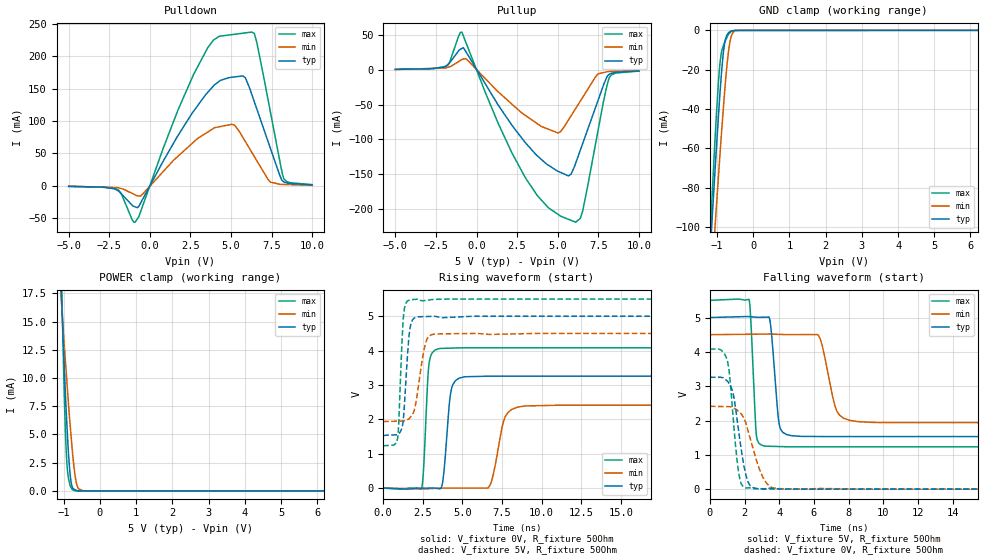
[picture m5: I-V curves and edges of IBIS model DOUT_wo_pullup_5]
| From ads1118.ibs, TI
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|   DOUT Model 5 V model Config Register bit3=1
[Model] DOUT_wo_pullup_5
|  Signals  DOUT/_DRDY(9)
|   bit 3 of the Config Registor is one
Model_type   3-state
Polarity   Non-Inverting
Enable   Active-Low
Vmeas = 2.5
Vref = 2.5
Cref = 15pF
Rref = 50
|   typ   min   max
|   (nom PVT)   (Fast PVT)   (slow PVT)
C_comp   1.8850880e-12  1.5248640e-12  2.2687600e-12
|   typ   min   max
|   (nom PVT)   (slow PVT)   (Fast PVT)
|C_comp (ON state)   2.6065280e-12  2.2751560e-12  4.1907400e-12
|C_comp (OFF state)   2.4127670e-12  2.2979320e-12  3.1339800e-12
| Where   nom PVT is  Nominal Process, 5V, 27C
|   Fast PVT is Strong or Fast Process, 5.5V, -40C
|   Slow PVT is Weak or Slow Process, 4.5V, 125C
| variable   typ   min   max
[Voltage Range]   5   4.5   5.5
|Operating Temperature   27   125   -40
[Temperature Range]   27   125   -40
[Pullup Reference]   5   4.5   5.5
[Pulldown Reference]   0   0   0
[Power Clamp Reference]   5   4.5   5.5
[GND Clamp Reference]   0   0   0
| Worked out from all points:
|   slope of the pulldown table from 0 to 0.75 V, typ, clamps not added: 21.6 ohm
|   slope of the pullup table from 0 to 0.75 V, typ, clamps not added: 25.9 ohm
|   GND clamp passes 1 mA (typ) near -0.67 V on its own axis
|   POWER clamp passes 1 mA (typ) near -0.81 V on its own axis
|   falling waveform, V_fixture 5V, R_fixture 50Ohm: 20-80 % time 327ps typ, 636ps min, 228ps max; typ from 5 V to 1.53 V
|   rising waveform, V_fixture 0V, R_fixture 50Ohm: 20-80 % time 342ps typ, 600ps min, 247ps max; typ from 0 V to 3.26 V
|   rising waveform, V_fixture 5V, R_fixture 50Ohm: 20-80 % time 296ps typ, 513ps min, 232ps max; typ from 1.53 V to 5 V
|   falling waveform, V_fixture 0V, R_fixture 50Ohm: 20-80 % time 566ps typ, 869ps min, 426ps max; typ from 3.26 V to 0 V
[Pulldown]
|   Voltage   I(typ)   I(min)   I(max)
-5V       -725.4uA   -519.1uA   -702.6uA
-1.982V   -7.151mA   -2.66mA    -5.43mA
-909.4mV  -32.26mA   -13.86mA   -55.8mA
1.742V    78.01mA    45.92mA    117.6mA
3.541V    143.5mA    82.63mA    211.9mA
5.072V    167.5mA    95.02mA    233.1mA
5.878V    166.7mA    68.45mA    235.8mA
6.259V    142.2mA    52.51mA    237mA
6.585V    118.6mA    38.88mA    221.1mA
7.411V    58.91mA    5.991mA    115.6mA
8.233V    6.609mA    2.243mA    12.24mA
10V       1.629mA    964.5uA    1.981mA
[GND Clamp]
|   Voltage   I(typ)   I(min)   I(max)
-5V       -1.404A    -1.291A    -1.638A
-1.23V    -125.5mA   -149mA     -118.8mA
-1.16V    -103.4mA   -129mA     -92.56mA
-1.138V   -96.43mA   -122.7mA   -84.61mA
-1.053V   -70.28mA   -99.07mA   -54.25mA
-967mV    -45.12mA   -75.71mA   -27.59mA
-909.4mV  -29.34mA   -60.41mA   -15.05mA
-788mV    -6.18mA    -30.54mA   -5.988mA
-676.7mV  -1.095mA   -9.66mA    -1.922mA
-610.9mV  -322.3uA   -3.251mA   -620.8uA
-396.5mV  -19.8uA    -16.1uA    -39.96uA
10V       0A         0A         0A
[Pullup]
|   Voltage   I(typ)   I(min)   I(max)
-5V       576.2uA    454.9uA    606.3uA
-1.857V   5.713mA    2.967mA    5.128mA
-918.9mV  30.55mA    14.49mA    54.26mA
1.339V    -51mA      -31.84mA   -77.38mA
3.009V    -105mA     -65.7mA    -155.4mA
5.03V     -146.3mA   -91.01mA   -208.3mA
5.667V    -152.8mA   -72.13mA   -215.4mA
6.099V    -135mA     -56.03mA   -219.4mA
6.534V    -106.4mA   -39.81mA   -203.7mA
7.48V     -44.41mA   -6.001mA   -88.09mA
8.16V     -6.895mA   -2.401mA   -12.17mA
10V       -1.584mA   -1.032mA   -1.861mA
[POWER Clamp]
|   Voltage   I(typ)   I(min)   I(max)
-5V       476.7mA    315.9mA    750.7mA
-1.076V   18.5mA     17.28mA    21.14mA
-1.053V   16.49mA    16.16mA    17.6mA
-975.5mV  10.16mA    12.42mA    7.317mA
-939.7mV  7.517mA    10.82mA    4.008mA
-909.4mV  5.624mA    9.474mA    2.261mA
-853.4mV  2.557mA    6.997mA    879.9uA
-806.9mV  984uA      5.205mA    354.1uA
-680.1mV  96.54uA    1.205mA    8.164uA
-596.9mV  5.069uA    198uA      8.1uA
-461.7mV  5.004uA    4.941uA    7.997uA
10V       0A         0A         0A
[Ramp]
R_load = 50
|   typ   min   max
dV/dt_r   1.95497/3.39673e-010   1.44792/5.95804e-010   2.44883/2.46868e-010
dV/dt_f   2.08044/3.23153e-010   1.53815/6.31012e-010   2.56058/2.27292e-010
[Falling Waveform]
V_fixture = 5V
V_fixture_min = 4.5V
V_fixture_max = 5.5V
R_fixture = 50Ohm
C_fixture = 0F
|   Time   V(typ)   V(min)   V(max)
0s        5V         4.5V       5.5V
2.265ns   5.026V     4.512V     5.519V
2.681ns   5.009V     4.515V     1.582V
3.182ns   5.01V      4.517V     1.253V
4.008ns   1.869V     4.509V     1.241V
4.712ns   1.557V     4.503V     1.233V
6.273ns   1.534V     4.472V     1.233V
7.317ns   1.533V     2.281V     1.233V
8.521ns   1.533V     1.968V     1.233V
50ns      1.533V     1.936V     1.232V
[Rising Waveform]
V_fixture = 0V
V_fixture_min = 0V
V_fixture_max = 0V
R_fixture = 50Ohm
C_fixture = 0F
|   Time   V(typ)   V(min)   V(max)
0s        829.1pV    1.313nV    740.3pV
2.423ns   -1.466mV   -20.94mV   -12.68mV
2.893ns   -445.1uV   -17.73mV   3.606V
3.555ns   -19.94mV   -1.51mV    4.062V
4.296ns   2.857V     -1.295mV   4.072V
5.126ns   3.238V     -1.053mV   4.081V
6.684ns   3.257V     37.03mV    4.081V
7.689ns   3.258V     2.062V     4.081V
8.914ns   3.258V     2.389V     4.081V
50ns      3.258V     2.413V     4.081V
[Rising Waveform]
V_fixture = 5V
V_fixture_min = 4.5V
V_fixture_max = 5.5V
R_fixture = 50Ohm
C_fixture = 0F
|   Time   V(typ)   V(min)   V(max)
0s        1.533V     1.936V     1.232V
906.7ps   1.563V     1.946V     1.44V
981.2ps   1.589V     1.947V     1.887V
1.289ns   2.089V     1.95V      5.037V
1.548ns   3.958V     1.996V     5.45V
1.72ns    4.713V     2.063V     5.481V
2.049ns   4.965V     2.443V     5.492V
2.69ns    4.991V     4.241V     5.461V
3.279ns   4.998V     4.486V     5.491V
50ns      5V         4.5V       5.5V
[Falling Waveform]
|Gnd
V_fixture = 0V
V_fixture_min = 0V
V_fixture_max = 0V
R_fixture = 50Ohm
C_fixture = 0F
|   Time   V(typ)   V(min)   V(max)
0s        3.258V     2.413V     4.081V
1.015ns   3.144V     2.404V     3.728V
1.145ns   3.055V     2.403V     3.293V
1.33ns    2.816V     2.373V     2.173V
1.647ns   1.747V     2.268V     528.8mV
2.077ns   418.6mV    1.924V     32.49mV
2.319ns   105.6mV    1.492V     36.06mV
3.037ns   8.508mV    369mV      8.224mV
3.9ns     10.23mV    16.15mV    286.2uV
50ns      829.1pV    1.313nV    740.3pV
